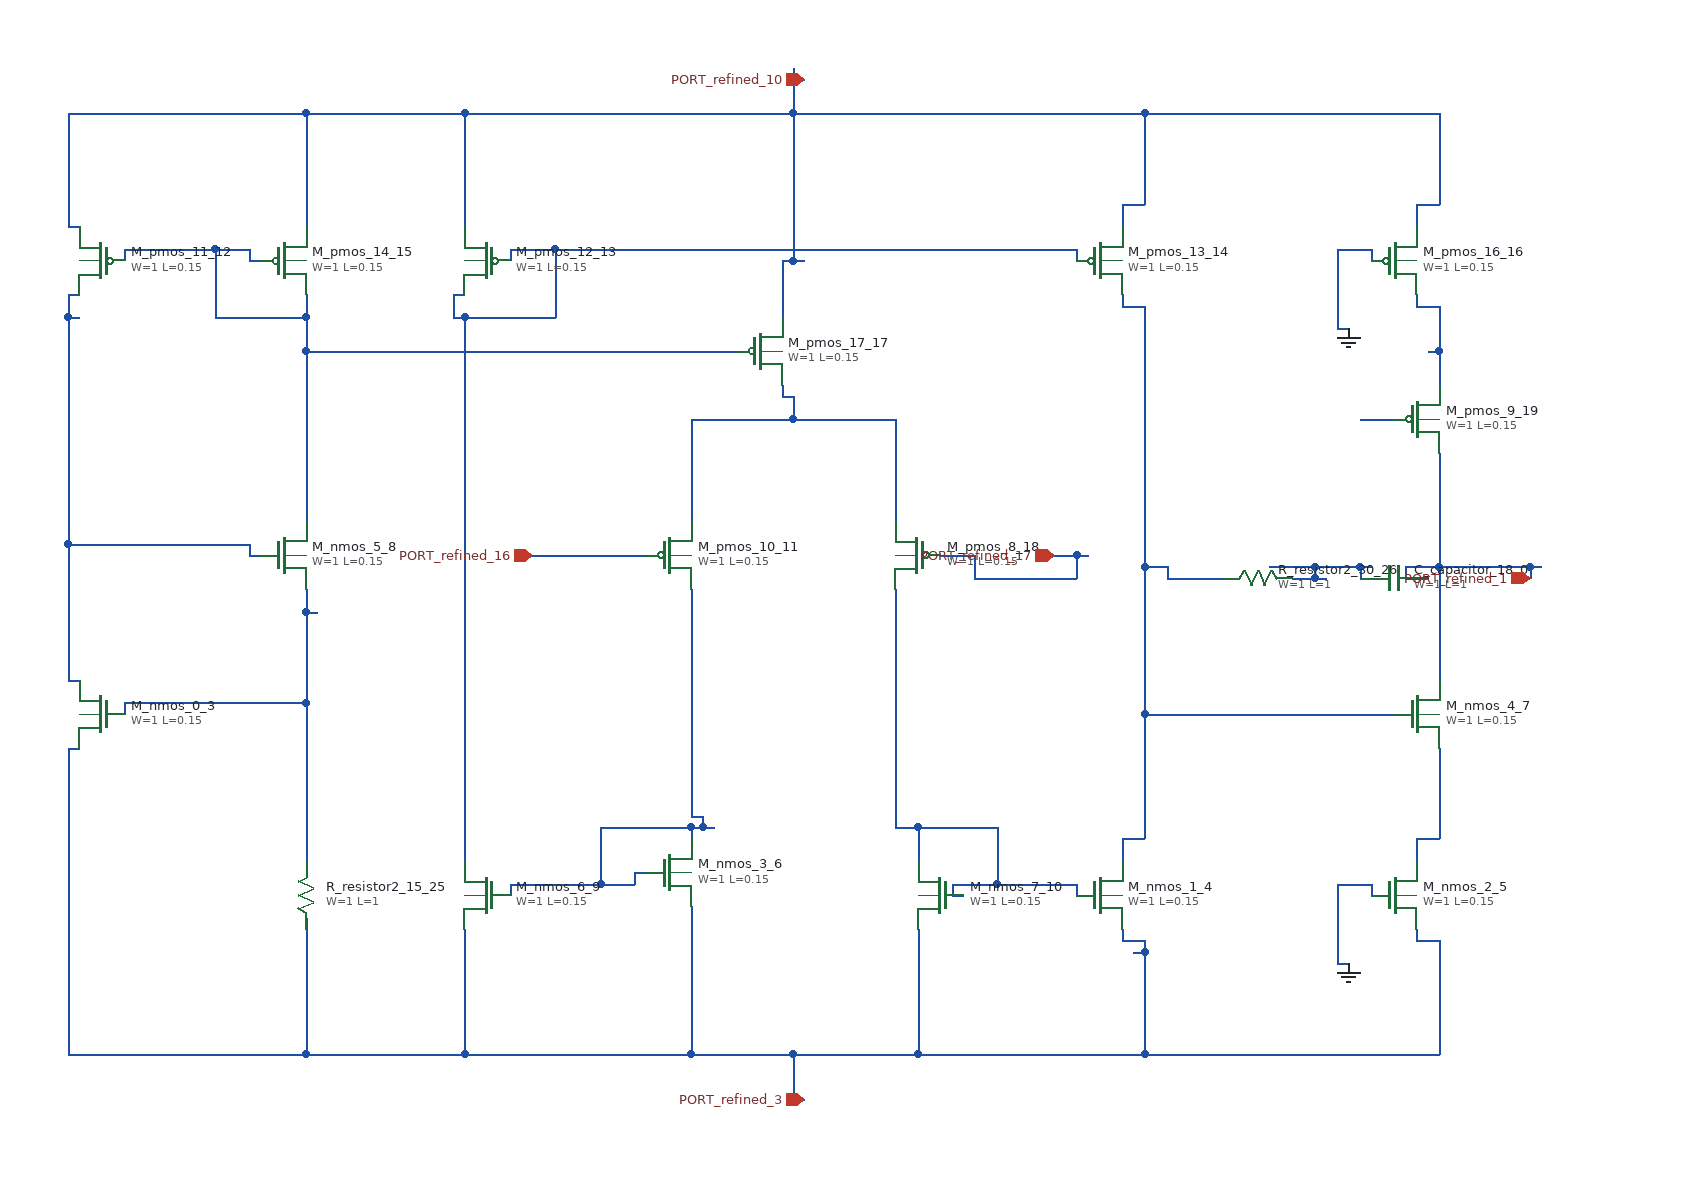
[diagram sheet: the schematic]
v {xschem version=3.4.8 file_version=1.2}
G {}
K {}
V {}
S {}
E {}
C {sky130_fd_pr/cap_mim_m3_1.sym} 1220 500 1 0 {name="C_capacitor_18_0" model=cap_mim_m3_1 W=1 L=1 MF=1 spiceprefix=X}
C {devices/gnd.sym} 1180 280 0 0 {name="l_gnd_19_1" lab="GND"}
C {devices/gnd.sym} 1180 840 0 0 {name="l_gnd_20_2" lab="GND"}
C {sky130_fd_pr/nfet3_01v8.sym} 80 620 0 1 {name="M_nmos_0_3"
W=1
L=0.15
body=GND
nf=1
mult=1
ad="expr('int((@nf + 1)/2) * @W / @nf * 0.29')"
pd="expr('2*int((@nf + 1)/2) * (@W / @nf + 0.29)')"
as="expr('int((@nf + 2)/2) * @W / @nf * 0.29')"
ps="expr('2*int((@nf + 2)/2) * (@W / @nf + 0.29)')"
nrd="expr('0.29 / @W ')" nrs="expr('0.29 / @W ')"
sa=0 sb=0 sd=0
model=nfet_01v8
spiceprefix=X
}
C {sky130_fd_pr/nfet3_01v8.sym} 960 780 0 0 {name="M_nmos_1_4"
W=1
L=0.15
body=GND
nf=1
mult=1
ad="expr('int((@nf + 1)/2) * @W / @nf * 0.29')"
pd="expr('2*int((@nf + 1)/2) * (@W / @nf + 0.29)')"
as="expr('int((@nf + 2)/2) * @W / @nf * 0.29')"
ps="expr('2*int((@nf + 2)/2) * (@W / @nf + 0.29)')"
nrd="expr('0.29 / @W ')" nrs="expr('0.29 / @W ')"
sa=0 sb=0 sd=0
model=nfet_01v8
spiceprefix=X
}
C {sky130_fd_pr/nfet3_01v8.sym} 1220 780 0 0 {name="M_nmos_2_5"
W=1
L=0.15
body=GND
nf=1
mult=1
ad="expr('int((@nf + 1)/2) * @W / @nf * 0.29')"
pd="expr('2*int((@nf + 1)/2) * (@W / @nf + 0.29)')"
as="expr('int((@nf + 2)/2) * @W / @nf * 0.29')"
ps="expr('2*int((@nf + 2)/2) * (@W / @nf + 0.29)')"
nrd="expr('0.29 / @W ')" nrs="expr('0.29 / @W ')"
sa=0 sb=0 sd=0
model=nfet_01v8
spiceprefix=X
}
C {sky130_fd_pr/nfet3_01v8.sym} 580 760 0 0 {name="M_nmos_3_6"
W=1
L=0.15
body=GND
nf=1
mult=1
ad="expr('int((@nf + 1)/2) * @W / @nf * 0.29')"
pd="expr('2*int((@nf + 1)/2) * (@W / @nf + 0.29)')"
as="expr('int((@nf + 2)/2) * @W / @nf * 0.29')"
ps="expr('2*int((@nf + 2)/2) * (@W / @nf + 0.29)')"
nrd="expr('0.29 / @W ')" nrs="expr('0.29 / @W ')"
sa=0 sb=0 sd=0
model=nfet_01v8
spiceprefix=X
}
C {sky130_fd_pr/nfet3_01v8.sym} 1240 620 0 0 {name="M_nmos_4_7"
W=1
L=0.15
body=GND
nf=1
mult=1
ad="expr('int((@nf + 1)/2) * @W / @nf * 0.29')"
pd="expr('2*int((@nf + 1)/2) * (@W / @nf + 0.29)')"
as="expr('int((@nf + 2)/2) * @W / @nf * 0.29')"
ps="expr('2*int((@nf + 2)/2) * (@W / @nf + 0.29)')"
nrd="expr('0.29 / @W ')" nrs="expr('0.29 / @W ')"
sa=0 sb=0 sd=0
model=nfet_01v8
spiceprefix=X
}
C {sky130_fd_pr/nfet3_01v8.sym} 240 480 0 0 {name="M_nmos_5_8"
W=1
L=0.15
body=GND
nf=1
mult=1
ad="expr('int((@nf + 1)/2) * @W / @nf * 0.29')"
pd="expr('2*int((@nf + 1)/2) * (@W / @nf + 0.29)')"
as="expr('int((@nf + 2)/2) * @W / @nf * 0.29')"
ps="expr('2*int((@nf + 2)/2) * (@W / @nf + 0.29)')"
nrd="expr('0.29 / @W ')" nrs="expr('0.29 / @W ')"
sa=0 sb=0 sd=0
model=nfet_01v8
spiceprefix=X
}
C {sky130_fd_pr/nfet3_01v8.sym} 420 780 0 1 {name="M_nmos_6_9"
W=1
L=0.15
body=GND
nf=1
mult=1
ad="expr('int((@nf + 1)/2) * @W / @nf * 0.29')"
pd="expr('2*int((@nf + 1)/2) * (@W / @nf + 0.29)')"
as="expr('int((@nf + 2)/2) * @W / @nf * 0.29')"
ps="expr('2*int((@nf + 2)/2) * (@W / @nf + 0.29)')"
nrd="expr('0.29 / @W ')" nrs="expr('0.29 / @W ')"
sa=0 sb=0 sd=0
model=nfet_01v8
spiceprefix=X
}
C {sky130_fd_pr/nfet3_01v8.sym} 820 780 0 1 {name="M_nmos_7_10"
W=1
L=0.15
body=GND
nf=1
mult=1
ad="expr('int((@nf + 1)/2) * @W / @nf * 0.29')"
pd="expr('2*int((@nf + 1)/2) * (@W / @nf + 0.29)')"
as="expr('int((@nf + 2)/2) * @W / @nf * 0.29')"
ps="expr('2*int((@nf + 2)/2) * (@W / @nf + 0.29)')"
nrd="expr('0.29 / @W ')" nrs="expr('0.29 / @W ')"
sa=0 sb=0 sd=0
model=nfet_01v8
spiceprefix=X
}
C {sky130_fd_pr/pfet3_01v8.sym} 580 480 0 0 {name="M_pmos_10_11"
W=1
L=0.15
body=VDD
nf=1
mult=1
ad="expr('int((@nf + 1)/2) * @W / @nf * 0.29')"
pd="expr('2*int((@nf + 1)/2) * (@W / @nf + 0.29)')"
as="expr('int((@nf + 2)/2) * @W / @nf * 0.29')"
ps="expr('2*int((@nf + 2)/2) * (@W / @nf + 0.29)')"
nrd="expr('0.29 / @W ')" nrs="expr('0.29 / @W ')"
sa=0 sb=0 sd=0
model=pfet_01v8
spiceprefix=X
}
C {sky130_fd_pr/pfet3_01v8.sym} 80 220 0 1 {name="M_pmos_11_12"
W=1
L=0.15
body=VDD
nf=1
mult=1
ad="expr('int((@nf + 1)/2) * @W / @nf * 0.29')"
pd="expr('2*int((@nf + 1)/2) * (@W / @nf + 0.29)')"
as="expr('int((@nf + 2)/2) * @W / @nf * 0.29')"
ps="expr('2*int((@nf + 2)/2) * (@W / @nf + 0.29)')"
nrd="expr('0.29 / @W ')" nrs="expr('0.29 / @W ')"
sa=0 sb=0 sd=0
model=pfet_01v8
spiceprefix=X
}
C {sky130_fd_pr/pfet3_01v8.sym} 420 220 0 1 {name="M_pmos_12_13"
W=1
L=0.15
body=VDD
nf=1
mult=1
ad="expr('int((@nf + 1)/2) * @W / @nf * 0.29')"
pd="expr('2*int((@nf + 1)/2) * (@W / @nf + 0.29)')"
as="expr('int((@nf + 2)/2) * @W / @nf * 0.29')"
ps="expr('2*int((@nf + 2)/2) * (@W / @nf + 0.29)')"
nrd="expr('0.29 / @W ')" nrs="expr('0.29 / @W ')"
sa=0 sb=0 sd=0
model=pfet_01v8
spiceprefix=X
}
C {sky130_fd_pr/pfet3_01v8.sym} 960 220 0 0 {name="M_pmos_13_14"
W=1
L=0.15
body=VDD
nf=1
mult=1
ad="expr('int((@nf + 1)/2) * @W / @nf * 0.29')"
pd="expr('2*int((@nf + 1)/2) * (@W / @nf + 0.29)')"
as="expr('int((@nf + 2)/2) * @W / @nf * 0.29')"
ps="expr('2*int((@nf + 2)/2) * (@W / @nf + 0.29)')"
nrd="expr('0.29 / @W ')" nrs="expr('0.29 / @W ')"
sa=0 sb=0 sd=0
model=pfet_01v8
spiceprefix=X
}
C {sky130_fd_pr/pfet3_01v8.sym} 240 220 0 0 {name="M_pmos_14_15"
W=1
L=0.15
body=VDD
nf=1
mult=1
ad="expr('int((@nf + 1)/2) * @W / @nf * 0.29')"
pd="expr('2*int((@nf + 1)/2) * (@W / @nf + 0.29)')"
as="expr('int((@nf + 2)/2) * @W / @nf * 0.29')"
ps="expr('2*int((@nf + 2)/2) * (@W / @nf + 0.29)')"
nrd="expr('0.29 / @W ')" nrs="expr('0.29 / @W ')"
sa=0 sb=0 sd=0
model=pfet_01v8
spiceprefix=X
}
C {sky130_fd_pr/pfet3_01v8.sym} 1220 220 0 0 {name="M_pmos_16_16"
W=1
L=0.15
body=VDD
nf=1
mult=1
ad="expr('int((@nf + 1)/2) * @W / @nf * 0.29')"
pd="expr('2*int((@nf + 1)/2) * (@W / @nf + 0.29)')"
as="expr('int((@nf + 2)/2) * @W / @nf * 0.29')"
ps="expr('2*int((@nf + 2)/2) * (@W / @nf + 0.29)')"
nrd="expr('0.29 / @W ')" nrs="expr('0.29 / @W ')"
sa=0 sb=0 sd=0
model=pfet_01v8
spiceprefix=X
}
C {sky130_fd_pr/pfet3_01v8.sym} 660 300 0 0 {name="M_pmos_17_17"
W=1
L=0.15
body=VDD
nf=1
mult=1
ad="expr('int((@nf + 1)/2) * @W / @nf * 0.29')"
pd="expr('2*int((@nf + 1)/2) * (@W / @nf + 0.29)')"
as="expr('int((@nf + 2)/2) * @W / @nf * 0.29')"
ps="expr('2*int((@nf + 2)/2) * (@W / @nf + 0.29)')"
nrd="expr('0.29 / @W ')" nrs="expr('0.29 / @W ')"
sa=0 sb=0 sd=0
model=pfet_01v8
spiceprefix=X
}
C {sky130_fd_pr/pfet3_01v8.sym} 800 480 0 1 {name="M_pmos_8_18"
W=1
L=0.15
body=VDD
nf=1
mult=1
ad="expr('int((@nf + 1)/2) * @W / @nf * 0.29')"
pd="expr('2*int((@nf + 1)/2) * (@W / @nf + 0.29)')"
as="expr('int((@nf + 2)/2) * @W / @nf * 0.29')"
ps="expr('2*int((@nf + 2)/2) * (@W / @nf + 0.29)')"
nrd="expr('0.29 / @W ')" nrs="expr('0.29 / @W ')"
sa=0 sb=0 sd=0
model=pfet_01v8
spiceprefix=X
}
C {sky130_fd_pr/pfet3_01v8.sym} 1240 360 0 0 {name="M_pmos_9_19"
W=1
L=0.15
body=VDD
nf=1
mult=1
ad="expr('int((@nf + 1)/2) * @W / @nf * 0.29')"
pd="expr('2*int((@nf + 1)/2) * (@W / @nf + 0.29)')"
as="expr('int((@nf + 2)/2) * @W / @nf * 0.29')"
ps="expr('2*int((@nf + 2)/2) * (@W / @nf + 0.29)')"
nrd="expr('0.29 / @W ')" nrs="expr('0.29 / @W ')"
sa=0 sb=0 sd=0
model=pfet_01v8
spiceprefix=X
}
C {devices/ipin.sym} 460 480 0 0 {name="p_port_22_20" lab="PORT_refined_16"}
C {devices/ipin.sym} 1340 500 0 0 {name="p_port_24_21" lab="PORT_refined_1"}
C {devices/ipin.sym} 700 60 0 0 {name="p_port_25_22" lab="PORT_refined_10"}
C {devices/ipin.sym} 700 960 0 0 {name="p_port_26_23" lab="PORT_refined_3"}
C {devices/ipin.sym} 920 480 0 0 {name="p_port_27_24" lab="PORT_refined_17"}
C {sky130_fd_pr/res_generic_po.sym} 260 780 2 0 {name="R_resistor2_15_25"
W=1
L=1
model=res_generic_po
spiceprefix=X
mult=1}
C {sky130_fd_pr/res_generic_po.sym} 1100 500 3 0 {name="R_resistor2_30_26"
W=1
L=1
model=res_generic_po
spiceprefix=X
mult=1}
N 1130 500 1150 500 {}
N 1150 500 1160 500 {}
N 1110 490 1150 490 {}
N 1150 490 1190 490 {}
N 1190 490 1200 490 {}
N 1150 500 1150 490 {}
N 1190 500 1190 490 {}
N 1230 500 1250 500 {}
N 1230 490 1260 490 {}
N 1260 490 1340 490 {}
N 1340 490 1350 490 {}
N 1230 500 1230 490 {}
N 1260 590 1260 490 {}
N 1260 490 1260 390 {}
N 1340 500 1340 490 {}
N 680 220 690 220 {}
N 690 220 700 220 {}
N 50 190 60 190 {}
N 980 170 1000 170 {}
N 1240 170 1260 170 {}
N 50 90 260 90 {}
N 260 90 400 90 {}
N 400 90 690 90 {}
N 690 90 1000 90 {}
N 1000 90 1260 90 {}
N 690 60 700 60 {}
N 50 190 50 90 {}
N 260 190 260 90 {}
N 400 190 400 90 {}
N 680 270 680 220 {}
N 690 220 690 90 {}
N 690 90 690 60 {}
N 690 60 690 50 {}
N 980 190 980 170 {}
N 1000 170 1000 90 {}
N 1240 190 1240 170 {}
N 1260 170 1260 90 {}
N 390 270 400 270 {}
N 400 270 480 270 {}
N 390 250 400 250 {}
N 440 210 480 210 {}
N 480 210 940 210 {}
N 390 270 390 250 {}
N 400 750 400 270 {}
N 440 220 440 210 {}
N 480 270 480 210 {}
N 940 220 940 210 {}
N 980 730 1000 730 {}
N 1000 620 1220 620 {}
N 1020 500 1070 500 {}
N 1000 490 1020 490 {}
N 980 260 1000 260 {}
N 980 750 980 730 {}
N 980 260 980 250 {}
N 1000 730 1000 620 {}
N 1000 620 1000 490 {}
N 1000 490 1000 260 {}
N 1020 500 1020 490 {}
N 1250 300 1260 300 {}
N 1240 260 1260 260 {}
N 1240 260 1240 250 {}
N 1260 330 1260 300 {}
N 1260 300 1260 260 {}
N 600 360 690 360 {}
N 690 360 780 360 {}
N 680 340 690 340 {}
N 600 450 600 360 {}
N 680 340 680 330 {}
N 690 360 690 340 {}
N 780 450 780 360 {}
N 1190 360 1220 360 {}
N 460 480 560 480 {}
N 850 500 940 500 {}
N 820 480 850 480 {}
N 920 480 940 480 {}
N 940 480 950 480 {}
N 850 500 850 480 {}
N 940 500 940 480 {}
N 1240 730 1260 730 {}
N 1240 750 1240 730 {}
N 1260 730 1260 650 {}
N 690 960 700 960 {}
N 50 920 260 920 {}
N 260 920 400 920 {}
N 400 920 600 920 {}
N 600 920 690 920 {}
N 690 920 800 920 {}
N 800 920 1000 920 {}
N 1000 920 1260 920 {}
N 990 830 1000 830 {}
N 980 820 1000 820 {}
N 1240 820 1260 820 {}
N 50 650 60 650 {}
N 50 920 50 650 {}
N 260 920 260 810 {}
N 260 810 260 800 {}
N 400 920 400 810 {}
N 600 920 600 790 {}
N 690 960 690 920 {}
N 800 920 800 810 {}
N 980 820 980 810 {}
N 1000 920 1000 830 {}
N 1000 830 1000 820 {}
N 1240 820 1240 810 {}
N 1260 920 1260 820 {}
N 1170 840 1180 840 {}
N 1170 770 1200 770 {}
N 1170 280 1180 280 {}
N 1170 210 1200 210 {}
N 1170 840 1170 770 {}
N 1170 280 1170 210 {}
N 1200 780 1200 770 {}
N 1200 220 1200 210 {}
N 440 770 520 770 {}
N 520 770 550 770 {}
N 550 760 560 760 {}
N 520 720 600 720 {}
N 600 720 610 720 {}
N 610 720 620 720 {}
N 600 710 610 710 {}
N 440 780 440 770 {}
N 520 770 520 720 {}
N 550 770 550 760 {}
N 600 730 600 720 {}
N 600 710 600 510 {}
N 610 720 610 710 {}
N 260 300 640 300 {}
N 180 270 260 270 {}
N 210 220 220 220 {}
N 100 210 180 210 {}
N 180 210 210 210 {}
N 100 220 100 210 {}
N 180 270 180 210 {}
N 210 220 210 210 {}
N 260 450 260 300 {}
N 260 300 260 270 {}
N 260 270 260 250 {}
N 100 610 260 610 {}
N 260 530 270 530 {}
N 100 620 100 610 {}
N 260 750 260 610 {}
N 260 610 260 530 {}
N 260 530 260 510 {}
N 50 590 60 590 {}
N 210 480 220 480 {}
N 50 470 210 470 {}
N 50 270 60 270 {}
N 50 250 60 250 {}
N 50 590 50 470 {}
N 50 470 50 270 {}
N 50 270 50 250 {}
N 210 480 210 470 {}
N 830 780 840 780 {}
N 830 770 870 770 {}
N 870 770 940 770 {}
N 780 720 800 720 {}
N 800 720 870 720 {}
N 780 720 780 510 {}
N 800 750 800 720 {}
N 830 780 830 770 {}
N 870 770 870 720 {}
N 940 780 940 770 {}
